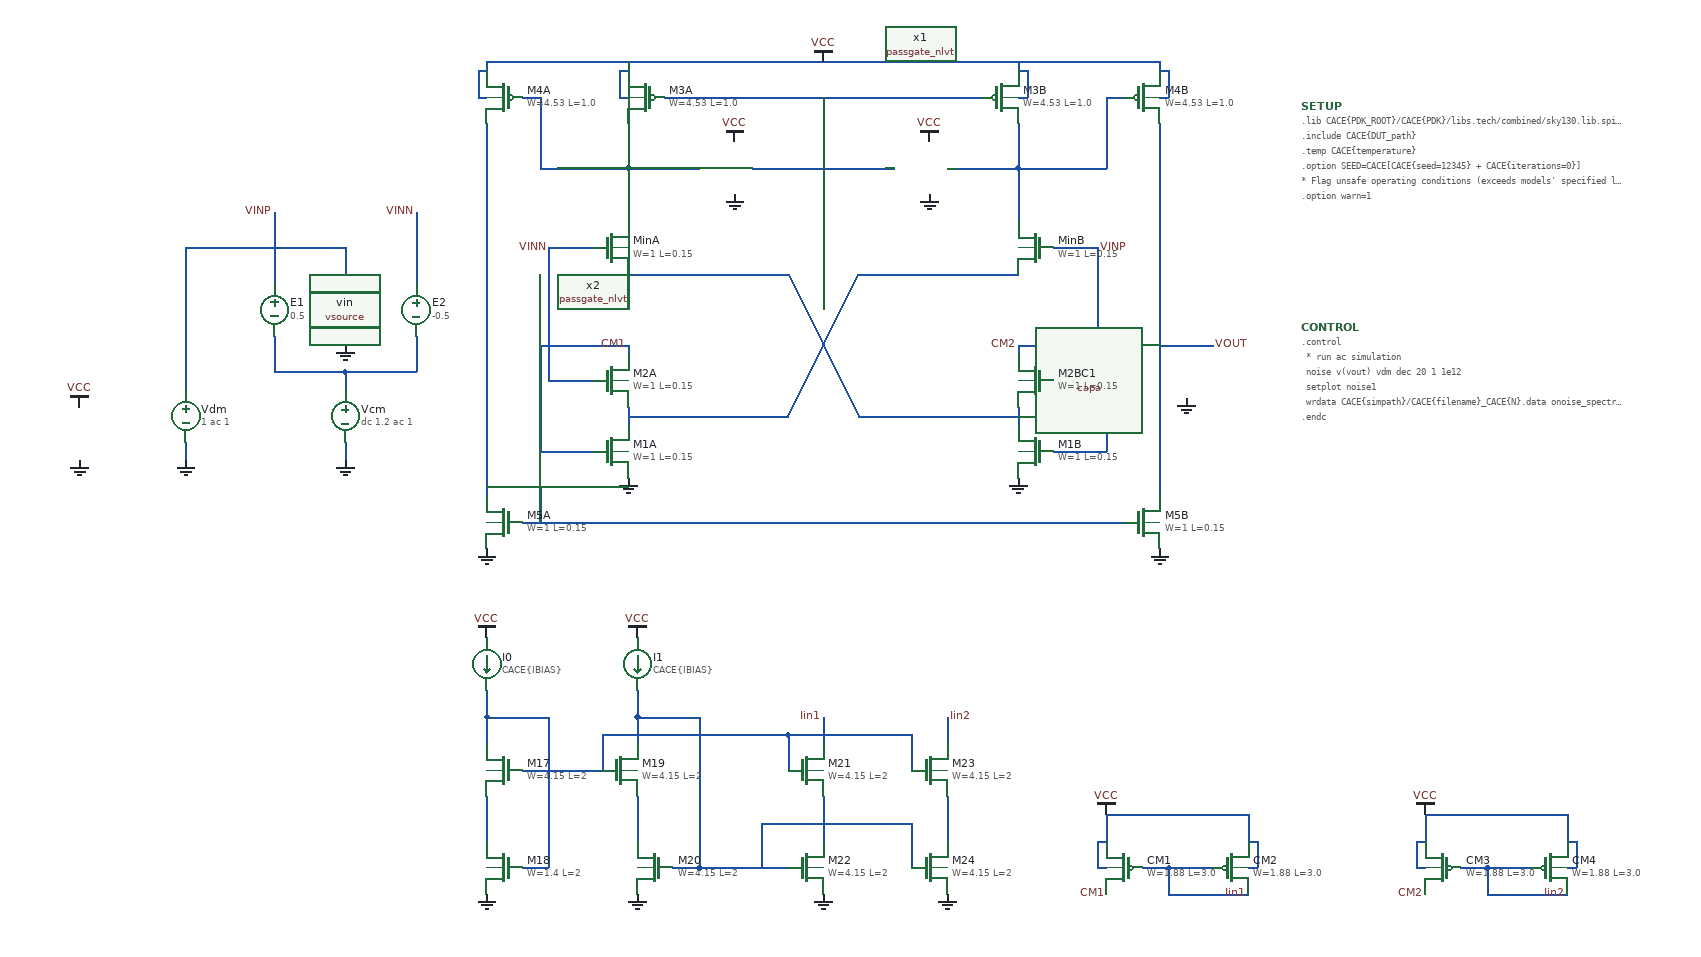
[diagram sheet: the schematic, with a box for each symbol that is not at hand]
v {xschem version=3.4.5 file_version=1.2
}
G {}
K {}
V {}
S {}
E {}
N -540 -60 -500 -60 {
lab=#net2}
N -720 -110 -720 50 {
lab=#net2}
N -720 -110 -540 -110 {
lab=#net2}
N -720 110 -720 130 {
lab=GND}
N -540 110 -540 130 {
lab=GND}
N -540 30 -460 30 {
lab=#net3}
N -540 30 -540 50 {
lab=#net3}
N -540 -20 -500 -20 {
lab=GND}
N -540 -20 -540 0 {
lab=GND}
N -620 -10 -620 30 {
lab=#net3}
N -460 -10 -460 30 {
lab=#net3}
N -540 -110 -540 -60 {
lab=#net2}
N -460 -150 -460 -70 {
lab=VINN}
N -620 -150 -620 -70 {
lab=VINP}
N -620 30 -540 30 {
lab=#net3}
N -580 -20 -540 -20 {
lab=GND}
N -580 -60 -540 -60 {
lab=#net2}
N 480 590 490 590 {
lab=VCC}
N 490 560 490 590 {
lab=VCC}
N 480 560 490 560 {
lab=VCC}
N 360 590 390 590 {
lab=Iin1}
N 390 590 440 590 {
lab=Iin1}
N 390 590 390 620 {
lab=Iin1}
N 390 620 480 620 {
lab=Iin1}
N 320 530 390 530 {
lab=VCC}
N 390 530 480 530 {
lab=VCC}
N 480 530 480 560 {
lab=VCC}
N 320 530 320 560 {
lab=VCC}
N 310 590 320 590 {
lab=VCC}
N 310 560 320 560 {
lab=VCC}
N 310 560 310 590 {
lab=VCC}
N 840 590 850 590 {
lab=VCC}
N 850 560 850 590 {
lab=VCC}
N 840 560 850 560 {
lab=VCC}
N 720 590 750 590 {
lab=Iin2}
N 750 590 800 590 {
lab=Iin2}
N 750 590 750 620 {
lab=Iin2}
N 750 620 840 620 {
lab=Iin2}
N 680 530 750 530 {
lab=VCC}
N 750 530 840 530 {
lab=VCC}
N 840 530 840 560 {
lab=VCC}
N 680 530 680 560 {
lab=VCC}
N 670 590 680 590 {
lab=VCC}
N 670 560 680 560 {
lab=VCC}
N 670 560 670 590 {
lab=VCC}
N -380 420 -380 450 {
lab=#net4}
N -380 510 -380 560 {
lab=#net5}
N -340 590 -310 590 {
lab=#net4}
N -310 420 -310 590 {
lab=#net4}
N -380 420 -310 420 {
lab=#net4}
N -210 420 -210 450 {
lab=#net6}
N -210 510 -210 560 {
lab=#net7}
N -170 590 -140 590 {
lab=#net6}
N -140 420 -140 590 {
lab=#net6}
N -210 420 -140 420 {
lab=#net6}
N 0 420 0 450 {
lab=Iin1}
N 0 510 0 560 {
lab=#net8}
N -340 480 -310 480 {
lab=#net4}
N -140 590 -40 590 {
lab=#net6}
N -380 390 -380 420 {
lab=#net4}
N -210 390 -210 420 {
lab=#net6}
N -310 480 -250 480 {
lab=#net4}
N -250 440 -250 480 {
lab=#net4}
N -250 440 -40 440 {
lab=#net4}
N -40 440 -40 480 {
lab=#net4}
N 140 420 140 450 {
lab=Iin2}
N 140 510 140 560 {
lab=#net9}
N 100 440 100 480 {
lab=#net4}
N -70 540 -70 590 {
lab=#net6}
N -70 540 100 540 {
lab=#net6}
N 100 540 100 590 {
lab=#net6}
N -40 440 100 440 {
lab=#net4}
N 220 0 220 10 {
lab=CM2}
N -320 0 -220 0 {
lab=CM1}
N -320 0 -320 120 {
lab=CM1}
N -320 120 -260 120 {
lab=CM1}
N 220 70 220 90 {
lab=#net1}
N -310 40 -260 40 {
lab=VINN}
N -310 -110 -260 -110 {
lab=VINN}
N 260 120 320 120 {
lab=CM2}
N 220 0 320 0 {
lab=CM2}
N 320 0 320 120 {
lab=CM2}
N 260 40 310 40 {
lab=VINP}
N 260 -110 310 -110 {
lab=VINP}
N -220 80 -40 80 {
lab=#net2}
N 40 -80 220 -80 {
lab=#net2}
N -220 -80 -40 -80 {
lab=#net1}
N 40 80 220 80 {
lab=#net1}
N 140 -200 220 -200 {
lab=#net3}
N -220 -200 -140 -200 {
lab=#net4}
N -80 -200 80 -200 {
lab=#net5}
N -180 -280 180 -280 {
lab=#net5}
N -380 -320 380 -320 {
lab=VCC}
N 320 -280 340 -280 {
lab=#net3}
N -340 -280 -320 -280 {
lab=#net4}
N -340 200 340 200 {
lab=#net6}
N -380 -250 -380 170 {
lab=#net6}
N -380 160 -320 160 {
lab=#net6}
N -320 160 -320 200 {
lab=#net6}
N 380 -250 380 170 {
lab=VOUT}
N -380 -320 -380 -310 {
lab=VCC}
N -220 -320 -220 -310 {
lab=VCC}
N 220 -320 220 -310 {
lab=VCC}
N 380 -320 380 -310 {
lab=VCC}
N 380 0 440 0 {
lab=VOUT}
N 220 -280 230 -280 {
lab=VCC}
N 230 -310 230 -280 {
lab=VCC}
N 220 -310 230 -310 {
lab=VCC}
N 380 -280 390 -280 {
lab=VCC}
N 390 -310 390 -280 {
lab=VCC}
N 380 -310 390 -310 {
lab=VCC}
N -230 -280 -220 -280 {
lab=VCC}
N -230 -310 -230 -280 {
lab=VCC}
N -230 -310 -220 -310 {
lab=VCC}
N -390 -280 -380 -280 {
lab=VCC}
N -390 -310 -390 -280 {
lab=VCC}
N -390 -310 -380 -310 {
lab=VCC}
N -220 0 -220 10 {
lab=CM1}
N -320 -280 -320 -200 {
lab=#net4}
N -320 -200 -220 -200 {
lab=#net4}
N 320 -280 320 -200 {
lab=#net3}
N 220 -200 320 -200 {
lab=#net3}
N -40 80 40 -80 {
lab=#net2}
N 220 -250 220 -200 {
lab=#net3}
N 220 -200 220 -140 {
lab=#net3}
N 310 -110 310 40 {
lab=VINP}
N -40 -80 40 80 {
lab=#net1}
N -310 -110 -310 40 {
lab=VINN}
N -220 -250 -220 -200 {
lab=#net4}
N -220 -200 -220 -140 {
lab=#net4}
N 0 -280 0 -200 {
lab=#net5}
N -220 70 -220 90 {
lab=#net2}
C {devices/lab_pin.sym} -620 -150 2 1 {name=p4 sig_type=std_logic lab=VINP
}
C {devices/lab_pin.sym} -460 -150 0 0 {name=p5 sig_type=std_logic lab=VINN}
C {devices/capa.sym} 410 30 0 0 {name=C1
m=1
value=CACE\{cl\}
footprint=1206
device="ceramic capacitor"}
C {devices/gnd.sym} 410 60 0 0 {name=l12 lab=GND}
C {devices/code_shown.sym} 540 -270 0 0 {name=SETUP
simulator=ngspice
only_toplevel=false
value="
.lib CACE\{PDK_ROOT\}/CACE\{PDK\}/libs.tech/combined/sky130.lib.spice CACE\{corner\}

.include CACE\{DUT_path\}

.temp CACE\{temperature\}

.option SEED=CACE[CACE\{seed=12345\} + CACE\{iterations=0\}]

* Flag unsafe operating conditions (exceeds models' specified limits)
.option warn=1
"}
C {devices/code_shown.sym} 540 -20 0 0 {name=CONTROL
simulator=ngspice
only_toplevel=false
value="
.control
    * run ac simulation
    noise v(vout) vdm dec 20 1 1e12 

    setplot noise1

    wrdata CACE\{simpath\}/CACE\{filename\}_CACE\{N\}.data onoise_spectrum inoise_spectrum

.endc
"}
C {devices/vcvs.sym} -620 -40 0 1 {name=E1 value=0.5}
C {devices/vcvs.sym} -460 -40 0 0 {name=E2 value=-0.5}
C {devices/vsource.sym} -720 80 0 1 {name=Vdm value="1 ac 1" savecurrent=false}
C {devices/vsource.sym} -540 80 0 0 {name=Vcm value="dc 1.2 ac 1" savecurrent=false}
C {devices/gnd.sym} -720 130 0 0 {name=l10 lab=GND}
C {devices/gnd.sym} -540 130 0 0 {name=l11 lab=GND}
C {devices/gnd.sym} -540 0 0 0 {name=l13 lab=GND}
C {devices/vsource.sym} -840 100 0 0 {name=vin value=CACE\{vcc\} savecurrent=false}
C {devices/gnd.sym} -840 130 0 0 {name=l14 lab=GND}
C {devices/vdd.sym} -840 70 0 0 {name=l15 lab=VCC}
C {devices/vdd.sym} 320 530 0 0 {name=l3 lab=VCC}
C {sky130_fd_pr/pfet_01v8_lvt.sym} 340 590 0 1 {name=CM1
W=1.88
L=3.0
nf=1
mult=2
ad="'int((nf+1)/2) * W/nf * 0.29'" 
pd="'2*int((nf+1)/2) * (W/nf + 0.29)'"
as="'int((nf+2)/2) * W/nf * 0.29'" 
ps="'2*int((nf+2)/2) * (W/nf + 0.29)'"
nrd="'0.29 / W'" nrs="'0.29 / W'"
sa=0 sb=0 sd=0
model=pfet_01v8_lvt
spiceprefix=X
}
C {sky130_fd_pr/pfet_01v8_lvt.sym} 460 590 0 0 {name=CM2
W=1.88
L=3.0
nf=1
mult=2
ad="'int((nf+1)/2) * W/nf * 0.29'" 
pd="'2*int((nf+1)/2) * (W/nf + 0.29)'"
as="'int((nf+2)/2) * W/nf * 0.29'" 
ps="'2*int((nf+2)/2) * (W/nf + 0.29)'"
nrd="'0.29 / W'" nrs="'0.29 / W'"
sa=0 sb=0 sd=0
model=pfet_01v8_lvt
spiceprefix=X
}
C {devices/lab_pin.sym} 320 620 3 0 {name=p9 sig_type=std_logic lab=CM1}
C {devices/vdd.sym} 680 530 0 0 {name=l7 lab=VCC}
C {sky130_fd_pr/pfet_01v8_lvt.sym} 700 590 0 1 {name=CM3
W=1.88
L=3.0
nf=1
mult=2
ad="'int((nf+1)/2) * W/nf * 0.29'" 
pd="'2*int((nf+1)/2) * (W/nf + 0.29)'"
as="'int((nf+2)/2) * W/nf * 0.29'" 
ps="'2*int((nf+2)/2) * (W/nf + 0.29)'"
nrd="'0.29 / W'" nrs="'0.29 / W'"
sa=0 sb=0 sd=0
model=pfet_01v8_lvt
spiceprefix=X
}
C {sky130_fd_pr/pfet_01v8_lvt.sym} 820 590 0 0 {name=CM4
W=1.88
L=3.0
nf=1
mult=2
ad="'int((nf+1)/2) * W/nf * 0.29'" 
pd="'2*int((nf+1)/2) * (W/nf + 0.29)'"
as="'int((nf+2)/2) * W/nf * 0.29'" 
ps="'2*int((nf+2)/2) * (W/nf + 0.29)'"
nrd="'0.29 / W'" nrs="'0.29 / W'"
sa=0 sb=0 sd=0
model=pfet_01v8_lvt
spiceprefix=X
}
C {devices/lab_pin.sym} 680 620 3 0 {name=p11 sig_type=std_logic lab=CM2}
C {devices/isource.sym} -380 360 0 0 {name=I0 value=CACE\{IBIAS\}}
C {devices/isource.sym} -210 360 0 0 {name=I1 value=CACE\{IBIAS\}}
C {sky130_fd_pr/nfet3_01v8.sym} -360 480 0 1 {name=M17
L=2
W=4.15
body=GND
nf=2
mult=1
ad="'int((nf+1)/2) * W/nf * 0.29'" 
pd="'2*int((nf+1)/2) * (W/nf + 0.29)'"
as="'int((nf+2)/2) * W/nf * 0.29'" 
ps="'2*int((nf+2)/2) * (W/nf + 0.29)'"
nrd="'0.29 / W'" nrs="'0.29 / W'"
sa=0 sb=0 sd=0
model=nfet_01v8
spiceprefix=X
}
C {sky130_fd_pr/nfet3_01v8.sym} -360 590 0 1 {name=M18
L=2
W=1.4
body=GND
nf=1
mult=1
ad="'int((nf+1)/2) * W/nf * 0.29'" 
pd="'2*int((nf+1)/2) * (W/nf + 0.29)'"
as="'int((nf+2)/2) * W/nf * 0.29'" 
ps="'2*int((nf+2)/2) * (W/nf + 0.29)'"
nrd="'0.29 / W'" nrs="'0.29 / W'"
sa=0 sb=0 sd=0
model=nfet_01v8
spiceprefix=X
}
C {sky130_fd_pr/nfet3_01v8.sym} -230 480 0 0 {name=M19
L=2
W=4.15
body=GND
nf=2
mult=1
ad="'int((nf+1)/2) * W/nf * 0.29'" 
pd="'2*int((nf+1)/2) * (W/nf + 0.29)'"
as="'int((nf+2)/2) * W/nf * 0.29'" 
ps="'2*int((nf+2)/2) * (W/nf + 0.29)'"
nrd="'0.29 / W'" nrs="'0.29 / W'"
sa=0 sb=0 sd=0
model=nfet_01v8
spiceprefix=X
}
C {sky130_fd_pr/nfet3_01v8.sym} -190 590 0 1 {name=M20
L=2
W=4.15
body=GND
nf=2
mult=1
ad="'int((nf+1)/2) * W/nf * 0.29'" 
pd="'2*int((nf+1)/2) * (W/nf + 0.29)'"
as="'int((nf+2)/2) * W/nf * 0.29'" 
ps="'2*int((nf+2)/2) * (W/nf + 0.29)'"
nrd="'0.29 / W'" nrs="'0.29 / W'"
sa=0 sb=0 sd=0
model=nfet_01v8
spiceprefix=X
}
C {sky130_fd_pr/nfet3_01v8.sym} -20 480 0 0 {name=M21
L=2
W=4.15
body=GND
nf=2
mult=1
ad="'int((nf+1)/2) * W/nf * 0.29'" 
pd="'2*int((nf+1)/2) * (W/nf + 0.29)'"
as="'int((nf+2)/2) * W/nf * 0.29'" 
ps="'2*int((nf+2)/2) * (W/nf + 0.29)'"
nrd="'0.29 / W'" nrs="'0.29 / W'"
sa=0 sb=0 sd=0
model=nfet_01v8
spiceprefix=X
}
C {sky130_fd_pr/nfet3_01v8.sym} -20 590 0 0 {name=M22
L=2
W=4.15
body=GND
nf=2
mult=1
ad="'int((nf+1)/2) * W/nf * 0.29'" 
pd="'2*int((nf+1)/2) * (W/nf + 0.29)'"
as="'int((nf+2)/2) * W/nf * 0.29'" 
ps="'2*int((nf+2)/2) * (W/nf + 0.29)'"
nrd="'0.29 / W'" nrs="'0.29 / W'"
sa=0 sb=0 sd=0
model=nfet_01v8
spiceprefix=X
}
C {devices/gnd.sym} 0 620 0 0 {name=l16 lab=GND}
C {devices/gnd.sym} -210 620 0 0 {name=l17 lab=GND}
C {devices/gnd.sym} -380 620 0 0 {name=l18 lab=GND}
C {devices/lab_pin.sym} 0 420 0 0 {name=p41 sig_type=std_logic lab=Iin1}
C {devices/lab_pin.sym} 140 420 0 1 {name=p42 sig_type=std_logic lab=Iin2}
C {sky130_fd_pr/nfet3_01v8.sym} 120 480 0 0 {name=M23
L=2
W=4.15
body=GND
nf=2
mult=1
ad="'int((nf+1)/2) * W/nf * 0.29'" 
pd="'2*int((nf+1)/2) * (W/nf + 0.29)'"
as="'int((nf+2)/2) * W/nf * 0.29'" 
ps="'2*int((nf+2)/2) * (W/nf + 0.29)'"
nrd="'0.29 / W'" nrs="'0.29 / W'"
sa=0 sb=0 sd=0
model=nfet_01v8
spiceprefix=X
}
C {sky130_fd_pr/nfet3_01v8.sym} 120 590 0 0 {name=M24
L=2
W=4.15
body=GND
nf=2
mult=1
ad="'int((nf+1)/2) * W/nf * 0.29'" 
pd="'2*int((nf+1)/2) * (W/nf + 0.29)'"
as="'int((nf+2)/2) * W/nf * 0.29'" 
ps="'2*int((nf+2)/2) * (W/nf + 0.29)'"
nrd="'0.29 / W'" nrs="'0.29 / W'"
sa=0 sb=0 sd=0
model=nfet_01v8
spiceprefix=X
}
C {devices/gnd.sym} 140 620 0 0 {name=l19 lab=GND}
C {devices/lab_pin.sym} 480 620 3 0 {name=p3 sig_type=std_logic lab=Iin1}
C {devices/lab_pin.sym} 840 620 1 1 {name=p10 sig_type=std_logic lab=Iin2}
C {devices/vdd.sym} -380 330 0 0 {name=l4 lab=VCC}
C {devices/vdd.sym} -210 330 0 0 {name=l5 lab=VCC}
C {devices/gnd.sym} 220 150 0 0 {name=l1 lab=GND}
C {devices/lab_pin.sym} -310 -110 0 0 {name=p1 sig_type=std_logic lab=VINN}
C {devices/gnd.sym} -220 150 0 1 {name=l2 lab=GND}
C {devices/lab_pin.sym} 310 -110 0 1 {name=p6 sig_type=std_logic lab=VINP
}
C {sky130_fd_pr/pfet_01v8_lvt.sym} 200 -280 0 0 {name=M3B
W=4.53
L=1.0
nf=1
mult=2
ad="'int((nf+1)/2) * W/nf * 0.29'" 
pd="'2*int((nf+1)/2) * (W/nf + 0.29)'"
as="'int((nf+2)/2) * W/nf * 0.29'" 
ps="'2*int((nf+2)/2) * (W/nf + 0.29)'"
nrd="'0.29 / W'" nrs="'0.29 / W'"
sa=0 sb=0 sd=0
model=pfet_01v8_lvt
spiceprefix=X
}
C {sky130_fd_pr/pfet_01v8_lvt.sym} -200 -280 0 1 {name=M3A
W=4.53
L=1.0
nf=1
mult=2
ad="'int((nf+1)/2) * W/nf * 0.29'" 
pd="'2*int((nf+1)/2) * (W/nf + 0.29)'"
as="'int((nf+2)/2) * W/nf * 0.29'" 
ps="'2*int((nf+2)/2) * (W/nf + 0.29)'"
nrd="'0.29 / W'" nrs="'0.29 / W'"
sa=0 sb=0 sd=0
model=pfet_01v8_lvt
spiceprefix=X
}
C {devices/vdd.sym} 0 -320 0 0 {name=l6 lab=VCC}
C {sky130_fd_pr/pfet_01v8_lvt.sym} 360 -280 0 0 {name=M4B
W=4.53
L=1.0
nf=1
mult=2
ad="'int((nf+1)/2) * W/nf * 0.29'" 
pd="'2*int((nf+1)/2) * (W/nf + 0.29)'"
as="'int((nf+2)/2) * W/nf * 0.29'" 
ps="'2*int((nf+2)/2) * (W/nf + 0.29)'"
nrd="'0.29 / W'" nrs="'0.29 / W'"
sa=0 sb=0 sd=0
model=pfet_01v8_lvt
spiceprefix=X
}
C {sky130_fd_pr/pfet_01v8_lvt.sym} -360 -280 0 1 {name=M4A
W=4.53
L=1.0
nf=1
mult=2
ad="'int((nf+1)/2) * W/nf * 0.29'" 
pd="'2*int((nf+1)/2) * (W/nf + 0.29)'"
as="'int((nf+2)/2) * W/nf * 0.29'" 
ps="'2*int((nf+2)/2) * (W/nf + 0.29)'"
nrd="'0.29 / W'" nrs="'0.29 / W'"
sa=0 sb=0 sd=0
model=pfet_01v8_lvt
spiceprefix=X
}
C {devices/gnd.sym} -380 230 0 1 {name=l8 lab=GND}
C {devices/gnd.sym} 380 230 0 1 {name=l9 lab=GND}
C {devices/lab_pin.sym} 440 0 2 0 {name=p2 sig_type=std_logic lab=VOUT}
C {sky130_tests/passgate_nlvt.sym} -100 -200 2 0 {name=x2 W_N=0.5 L_N=4 W_P=3 L_P=4 VCCBPIN=VCC VSSBPIN=VSS m=1}
C {sky130_tests/passgate_nlvt.sym} 120 -200 2 1 {name=x1 W_N=0.5 L_N=4 W_P=3 L_P=4 VCCBPIN=VCC VSSBPIN=VSS m=1}
C {devices/vdd.sym} -100 -230 0 0 {name=l20 lab=VCC}
C {devices/vdd.sym} 120 -230 0 0 {name=l21 lab=VCC}
C {devices/gnd.sym} -100 -170 0 1 {name=l22 lab=GND}
C {devices/gnd.sym} 120 -170 0 0 {name=l23 lab=GND}
C {devices/lab_pin.sym} -220 0 1 0 {name=p8 sig_type=std_logic lab=CM1}
C {devices/lab_pin.sym} 220 0 1 0 {name=p7 sig_type=std_logic lab=CM2}
C {sky130_fd_pr/nfet3_01v8.sym} -240 40 0 0 {name=M2A
L=0.15
W=1
nf=1
mult=1
body=GND
ad="'int((nf+1)/2) * W/nf * 0.29'" 
pd="'2*int((nf+1)/2) * (W/nf + 0.29)'"
as="'int((nf+2)/2) * W/nf * 0.29'" 
ps="'2*int((nf+2)/2) * (W/nf + 0.29)'"
nrd="'0.29 / W'" nrs="'0.29 / W'"
sa=0 sb=0 sd=0
model=nfet_01v8
spiceprefix=X
}
C {sky130_fd_pr/nfet3_01v8.sym} -240 120 0 0 {name=M1A
L=0.15
W=1
nf=1
mult=1
body=GND
ad="'int((nf+1)/2) * W/nf * 0.29'" 
pd="'2*int((nf+1)/2) * (W/nf + 0.29)'"
as="'int((nf+2)/2) * W/nf * 0.29'" 
ps="'2*int((nf+2)/2) * (W/nf + 0.29)'"
nrd="'0.29 / W'" nrs="'0.29 / W'"
sa=0 sb=0 sd=0
model=nfet_01v8
spiceprefix=X
}
C {sky130_fd_pr/nfet3_01v8.sym} 240 40 0 1 {name=M2B
L=0.15
W=1
nf=1
mult=1
body=GND
ad="'int((nf+1)/2) * W/nf * 0.29'" 
pd="'2*int((nf+1)/2) * (W/nf + 0.29)'"
as="'int((nf+2)/2) * W/nf * 0.29'" 
ps="'2*int((nf+2)/2) * (W/nf + 0.29)'"
nrd="'0.29 / W'" nrs="'0.29 / W'"
sa=0 sb=0 sd=0
model=nfet_01v8
spiceprefix=X
}
C {sky130_fd_pr/nfet3_01v8.sym} 240 120 0 1 {name=M1B
L=0.15
W=1
nf=1
mult=1
body=GND
ad="'int((nf+1)/2) * W/nf * 0.29'" 
pd="'2*int((nf+1)/2) * (W/nf + 0.29)'"
as="'int((nf+2)/2) * W/nf * 0.29'" 
ps="'2*int((nf+2)/2) * (W/nf + 0.29)'"
nrd="'0.29 / W'" nrs="'0.29 / W'"
sa=0 sb=0 sd=0
model=nfet_01v8
spiceprefix=X
}
C {sky130_fd_pr/nfet3_01v8.sym} -240 -110 0 0 {name=MinA
L=0.15
W=1
nf=1
mult=1
body=GND
ad="'int((nf+1)/2) * W/nf * 0.29'" 
pd="'2*int((nf+1)/2) * (W/nf + 0.29)'"
as="'int((nf+2)/2) * W/nf * 0.29'" 
ps="'2*int((nf+2)/2) * (W/nf + 0.29)'"
nrd="'0.29 / W'" nrs="'0.29 / W'"
sa=0 sb=0 sd=0
model=nfet_01v8
spiceprefix=X
}
C {sky130_fd_pr/nfet3_01v8.sym} 240 -110 0 1 {name=MinB
L=0.15
W=1
nf=1
mult=1
body=GND
ad="'int((nf+1)/2) * W/nf * 0.29'" 
pd="'2*int((nf+1)/2) * (W/nf + 0.29)'"
as="'int((nf+2)/2) * W/nf * 0.29'" 
ps="'2*int((nf+2)/2) * (W/nf + 0.29)'"
nrd="'0.29 / W'" nrs="'0.29 / W'"
sa=0 sb=0 sd=0
model=nfet_01v8
spiceprefix=X
}
C {sky130_fd_pr/nfet3_01v8.sym} -360 200 0 1 {name=M5A
L=0.15
W=1
nf=1
mult=1
body=GND
ad="'int((nf+1)/2) * W/nf * 0.29'" 
pd="'2*int((nf+1)/2) * (W/nf + 0.29)'"
as="'int((nf+2)/2) * W/nf * 0.29'" 
ps="'2*int((nf+2)/2) * (W/nf + 0.29)'"
nrd="'0.29 / W'" nrs="'0.29 / W'"
sa=0 sb=0 sd=0
model=nfet_01v8
spiceprefix=X
}
C {sky130_fd_pr/nfet3_01v8.sym} 360 200 0 0 {name=M5B
L=0.15
W=1
nf=1
mult=1
body=GND
ad="'int((nf+1)/2) * W/nf * 0.29'" 
pd="'2*int((nf+1)/2) * (W/nf + 0.29)'"
as="'int((nf+2)/2) * W/nf * 0.29'" 
ps="'2*int((nf+2)/2) * (W/nf + 0.29)'"
nrd="'0.29 / W'" nrs="'0.29 / W'"
sa=0 sb=0 sd=0
model=nfet_01v8
spiceprefix=X
}
